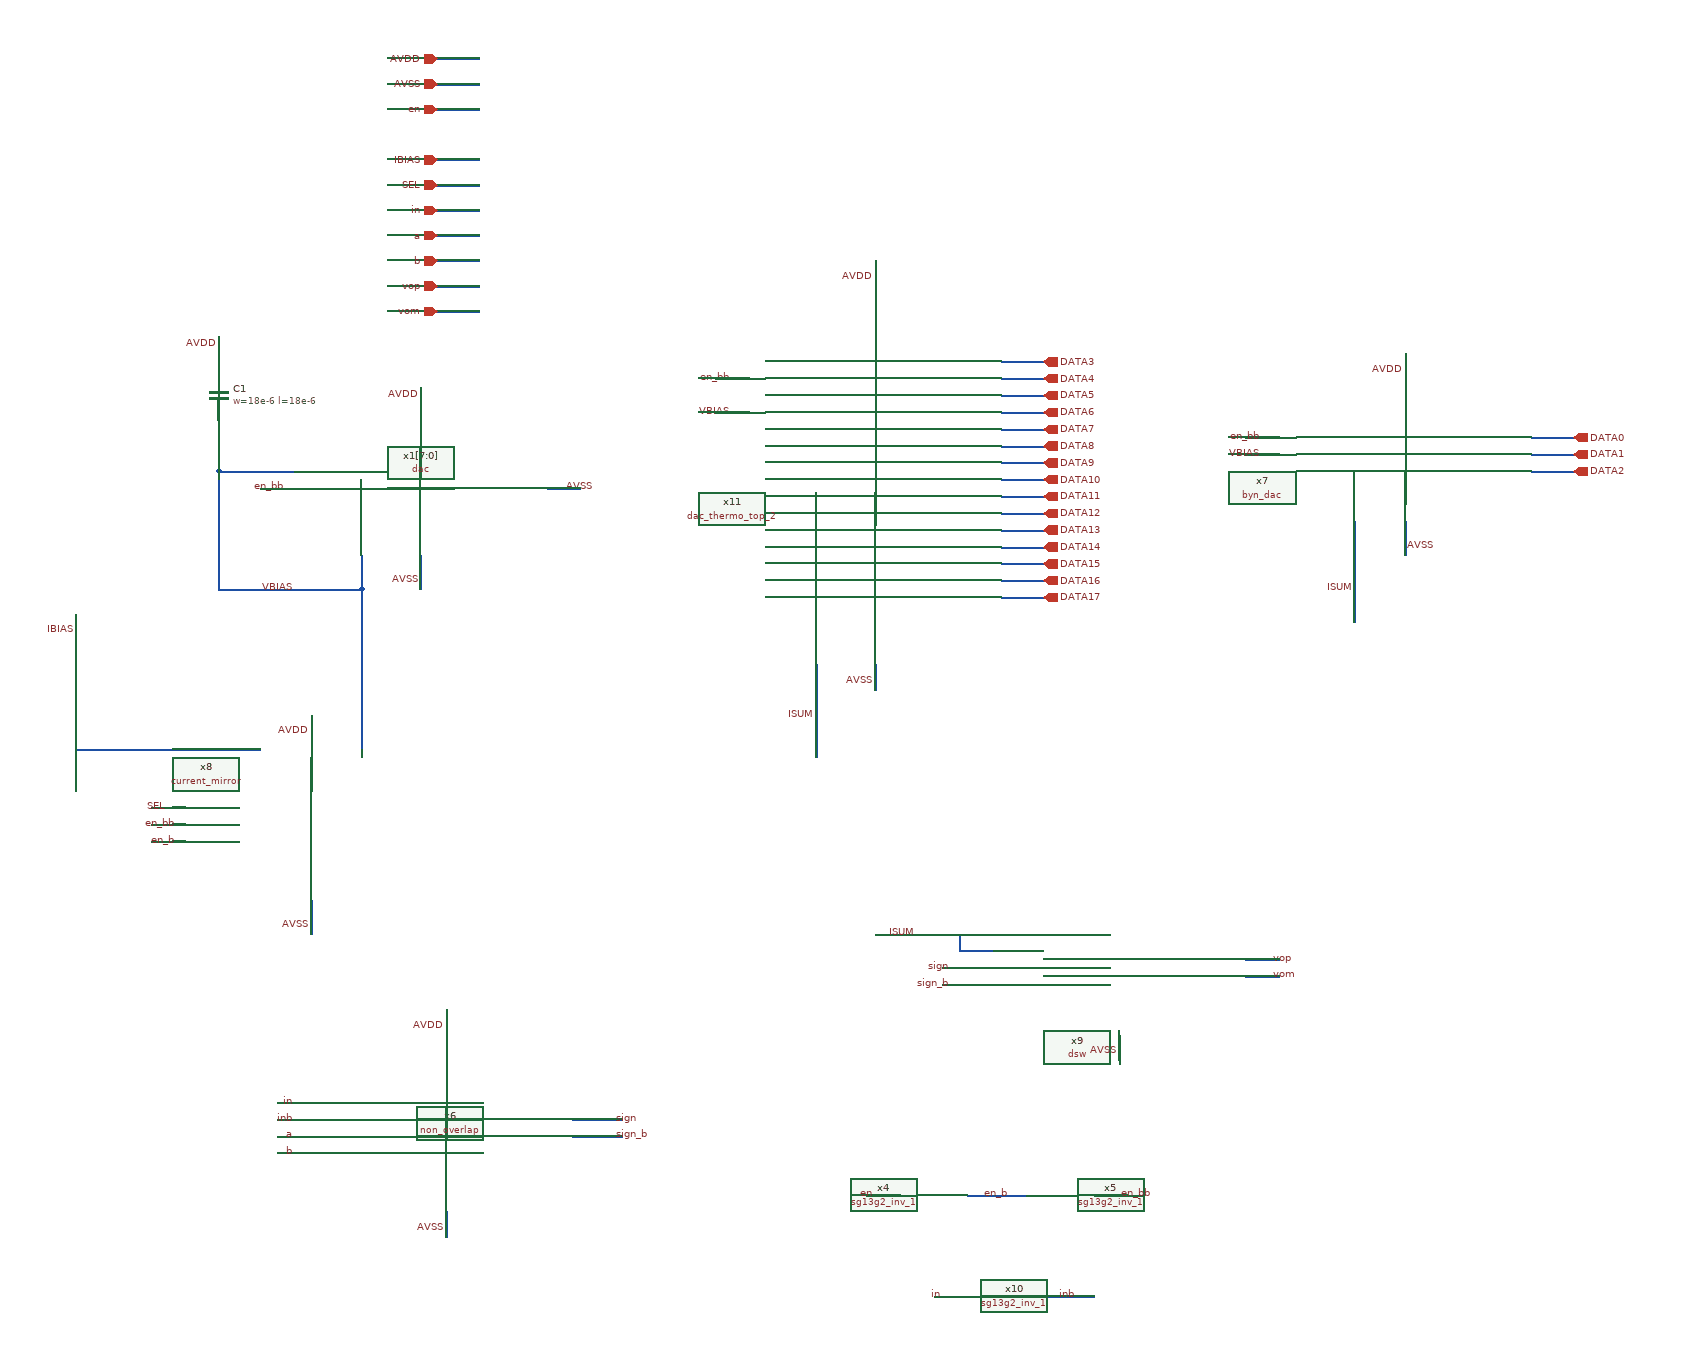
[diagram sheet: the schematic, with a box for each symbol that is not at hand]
v {xschem version=3.4.8RC file_version=1.3}
G {}
K {}
V {}
S {}
F {}
E {}
N 790 -850 790 -810 {lab=AVDD}
N 920 -1240 920 -1200 {lab=AVDD}
N 790 -630 790 -590 {lab=AVSS}
N 600 -740 640 -740 {lab=SEL}
N 600 -720 640 -720 {lab=en_bb}
N 600 -700 640 -700 {lab=en_b}
N 730 -1120 770 -1120 {lab=en_bb}
N 1070 -1120 1110 -1120 {lab=AVSS}
N 920 -1040 920 -1000 {lab=AVSS}
N 1460 -1390 1460 -1350 {lab=AVDD}
N 1270 -1210 1310 -1210 {lab=VBIAS}
N 1270 -1250 1310 -1250 {lab=en_bb}
N 1460 -910 1460 -880 {lab=AVSS}
N 1450 -280 1490 -280 {lab=en}
N 1570 -280 1640 -280 {lab=en_b}
N 1720 -280 1760 -280 {lab=en_bb}
N 680 -1140 770 -1140 {lab=VBIAS}
N 680 -1140 680 -1000 {lab=VBIAS}
N 680 -1000 850 -1000 {lab=VBIAS}
N 850 -1040 850 -1000 {lab=VBIAS}
N 1530 -160 1570 -160 {lab=in}
N 1650 -160 1720 -160 {lab=inb}
N 1100 -370 1160 -370 {lab=sign}
N 1100 -350 1160 -350 {lab=sign_b}
N 950 -260 950 -230 {lab=AVSS}
N 950 -500 950 -460 {lab=AVDD}
N 750 -390 800 -390 {lab=in}
N 750 -370 800 -370 {lab=inb}
N 750 -350 800 -350 {lab=a}
N 750 -330 800 -330 {lab=b}
N 2090 -1080 2090 -1040 {lab=AVSS}
N 2090 -1280 2090 -1240 {lab=AVDD}
N 1900 -1160 1940 -1160 {lab=VBIAS}
N 1900 -1180 1940 -1180 {lab=en_bb}
N 510 -810 730 -810 {lab=IBIAS}
N 510 -970 510 -810 {lab=IBIAS}
N 850 -1000 850 -810 {lab=VBIAS}
N 1540 -550 1600 -550 {lab=sign}
N 1540 -530 1600 -530 {lab=sign_b}
N 1900 -560 1940 -560 {lab=vop}
N 1900 -540 1940 -540 {lab=vom}
N 1750 -470 1750 -440 {lab=AVSS}
N 1560 -570 1600 -570 {lab=ISUM}
N 1560 -590 1560 -570 {lab=ISUM}
N 1390 -910 1390 -800 {lab=ISUM}
N 1460 -590 1560 -590 {lab=ISUM}
N 2030 -1080 2030 -960 {lab=ISUM}
N 940 -1630 990 -1630 {lab=AVDD}
N 940 -1600 990 -1600 {lab=AVSS}
N 1610 -1270 1660 -1270 {lab=DATA3}
N 940 -1570 990 -1570 {lab=en}
N 1610 -1250 1660 -1250 {lab=DATA4}
N 1610 -1230 1660 -1230 {lab=DATA5}
N 1610 -1210 1660 -1210 {lab=DATA6}
N 1610 -1190 1660 -1190 {lab=DATA7}
N 1610 -1170 1660 -1170 {lab=DATA8}
N 1610 -1150 1660 -1150 {lab=DATA9}
N 1610 -1130 1660 -1130 {lab=DATA10}
N 1610 -1110 1660 -1110 {lab=DATA11}
N 1610 -1090 1660 -1090 {lab=DATA12}
N 1610 -1070 1660 -1070 {lab=DATA13}
N 1610 -1050 1660 -1050 {lab=DATA14}
N 1610 -1030 1660 -1030 {lab=DATA15}
N 1610 -1010 1660 -1010 {lab=DATA16}
N 1610 -990 1660 -990 {lab=DATA17}
N 940 -1510 990 -1510 {lab=IBIAS}
N 940 -1480 990 -1480 {lab=SEL}
N 940 -1450 990 -1450 {lab=in}
N 940 -1420 990 -1420 {lab=a}
N 940 -1390 990 -1390 {lab=b}
N 940 -1360 990 -1360 {lab=vop}
N 940 -1330 990 -1330 {lab=vom}
N 2240 -1180 2290 -1180 {lab=DATA0}
N 2240 -1160 2290 -1160 {lab=DATA1}
N 2240 -1140 2290 -1140 {lab=DATA2}
N 680 -1200 680 -1140 {lab=VBIAS}
N 680 -1300 680 -1260 {lab=AVDD}
C {current_mirror.sym} 790 -720 0 0 {name=x8}
C {lab_wire.sym} 790 -830 0 0 {name=p12 sig_type=std_logic lab=AVDD}
C {lab_wire.sym} 770 -1000 0 0 {name=p13 sig_type=std_logic lab=VBIAS}
C {lab_wire.sym} 620 -740 0 0 {name=p14 sig_type=std_logic lab=SEL}
C {lab_wire.sym} 630 -720 0 0 {name=p15 sig_type=std_logic lab=en_bb}
C {lab_wire.sym} 630 -700 0 0 {name=p16 sig_type=std_logic lab=en_b}
C {lab_wire.sym} 790 -600 0 0 {name=p17 sig_type=std_logic lab=AVSS}
C {lab_wire.sym} 920 -1010 0 0 {name=p18 sig_type=std_logic lab=AVSS}
C {lab_wire.sym} 920 -1230 0 0 {name=p19 sig_type=std_logic lab=AVDD}
C {lab_wire.sym} 1460 -1370 0 0 {name=p20 sig_type=std_logic lab=AVDD}
C {lab_wire.sym} 760 -1120 0 0 {name=p21 sig_type=std_logic lab=en_bb}
C {lab_wire.sym} 1290 -1210 0 0 {name=p22 sig_type=std_logic lab=VBIAS}
C {lab_wire.sym} 1290 -1250 0 0 {name=p23 sig_type=std_logic lab=en_bb}
C {lab_wire.sym} 1090 -1120 0 1 {name=p28 sig_type=std_logic lab=AVSS}
C {sg13g2_stdcells/sg13g2_inv_1.sym} 1530 -280 0 0 {name=x4 VDD=AVDD VSS=AVSS prefix=sg13g2_ }
C {lab_wire.sym} 1460 -280 0 0 {name=p44 sig_type=std_logic lab=en}
C {sg13g2_stdcells/sg13g2_inv_1.sym} 1680 -280 0 0 {name=x5 VDD=AVDD VSS=AVSS prefix=sg13g2_ }
C {lab_wire.sym} 1620 -280 0 0 {name=p45 sig_type=std_logic lab=en_b}
C {lab_wire.sym} 510 -950 0 0 {name=p24 sig_type=std_logic lab=IBIAS}
C {lab_wire.sym} 1750 -280 0 1 {name=p50 sig_type=std_logic lab=en_bb}
C {sg13g2_stdcells/sg13g2_inv_1.sym} 1610 -160 0 0 {name=x10 VDD=AVDD VSS=AVSS prefix=sg13g2_ }
C {lab_wire.sym} 1540 -160 0 0 {name=p57 sig_type=std_logic lab=in}
C {lab_wire.sym} 1700 -160 0 0 {name=p58 sig_type=std_logic lab=inb}
C {lab_wire.sym} 1460 -890 1 1 {name=p29 sig_type=std_logic lab=AVSS}
C {lab_wire.sym} 1390 -850 0 0 {name=p26 sig_type=std_logic lab=ISUM}
C {non_overlap.sym} 950 -360 0 0 {name=x6}
C {lab_wire.sym} 1150 -370 0 1 {name=p30 sig_type=std_logic lab=sign}
C {lab_wire.sym} 1150 -350 0 1 {name=p31 sig_type=std_logic lab=sign_b}
C {lab_wire.sym} 950 -240 0 0 {name=p32 sig_type=std_logic lab=AVSS}
C {lab_wire.sym} 950 -480 0 0 {name=p33 sig_type=std_logic lab=AVDD}
C {lab_wire.sym} 770 -370 0 0 {name=p34 sig_type=std_logic lab=inb}
C {lab_wire.sym} 770 -390 0 0 {name=p35 sig_type=std_logic lab=in}
C {lab_wire.sym} 770 -350 0 0 {name=p51 sig_type=std_logic lab=a}
C {lab_wire.sym} 770 -330 0 0 {name=p52 sig_type=std_logic lab=b}
C {byn_dac.sym} 2090 -1160 0 0 {name=x7}
C {lab_wire.sym} 2090 -1050 0 1 {name=p53 sig_type=std_logic lab=AVSS}
C {lab_wire.sym} 2090 -1260 0 0 {name=p54 sig_type=std_logic lab=AVDD}
C {lab_wire.sym} 1920 -1160 0 0 {name=p59 sig_type=std_logic lab=VBIAS}
C {lab_wire.sym} 1920 -1180 0 0 {name=p66 sig_type=std_logic lab=en_bb}
C {lab_wire.sym} 2030 -1000 0 0 {name=p67 sig_type=std_logic lab=ISUM}
C {lab_wire.sym} 1930 -560 0 1 {name=p68 sig_type=std_logic lab=vop}
C {dsw.sym} 1750 -550 0 0 {name=x9}
C {lab_wire.sym} 1930 -540 0 1 {name=p107 sig_type=std_logic lab=vom}
C {lab_wire.sym} 1750 -450 0 0 {name=p108 sig_type=std_logic lab=AVSS}
C {lab_wire.sym} 1550 -550 0 0 {name=p109 sig_type=std_logic lab=sign}
C {lab_wire.sym} 1550 -530 0 0 {name=p110 sig_type=std_logic lab=sign_b}
C {lab_wire.sym} 1510 -590 0 0 {name=p113 sig_type=std_logic lab=ISUM}
C {dac_thermo_top_2.sym} 1460 -1140 0 0 {name=x11}
C {dac.sym} 920 -1120 0 0 {name=x1[7:0]}
C {iopin.sym} 940 -1630 2 0 {name=p721 lab=AVDD}
C {iopin.sym} 940 -1600 2 0 {name=p722 lab=AVSS}
C {iopin.sym} 940 -1570 2 0 {name=p724 lab=en}
C {iopin.sym} 1660 -1250 2 1 {name=p725 lab=DATA4}
C {iopin.sym} 1660 -1270 2 1 {name=p727 lab=DATA3}
C {iopin.sym} 1660 -1230 2 1 {name=p728 lab=DATA5}
C {iopin.sym} 1660 -1190 2 1 {name=p729 lab=DATA7}
C {iopin.sym} 1660 -1210 2 1 {name=p730 lab=DATA6}
C {iopin.sym} 1660 -1170 2 1 {name=p731 lab=DATA8}
C {iopin.sym} 1660 -1150 2 1 {name=p732 lab=DATA9}
C {iopin.sym} 1660 -1130 2 1 {name=p733 lab=DATA10}
C {iopin.sym} 1660 -1090 2 1 {name=p734 lab=DATA12}
C {iopin.sym} 1660 -1110 2 1 {name=p735 lab=DATA11}
C {iopin.sym} 1660 -1070 2 1 {name=p736 lab=DATA13}
C {iopin.sym} 1660 -1050 2 1 {name=p737 lab=DATA14}
C {iopin.sym} 1660 -1030 2 1 {name=p738 lab=DATA15}
C {iopin.sym} 1660 -1010 2 1 {name=p739 lab=DATA16}
C {iopin.sym} 1660 -990 2 1 {name=p740 lab=DATA17}
C {iopin.sym} 940 -1510 2 0 {name=p1 lab=IBIAS}
C {iopin.sym} 940 -1480 2 0 {name=p2 lab=SEL}
C {iopin.sym} 940 -1450 2 0 {name=p3 lab=in}
C {iopin.sym} 940 -1420 2 0 {name=p4 lab=a}
C {iopin.sym} 940 -1390 2 0 {name=p5 lab=b}
C {iopin.sym} 940 -1360 2 0 {name=p6 lab=vop}
C {iopin.sym} 940 -1330 2 0 {name=p7 lab=vom}
C {iopin.sym} 2290 -1160 2 1 {name=p8 lab=DATA1}
C {iopin.sym} 2290 -1180 2 1 {name=p9 lab=DATA0}
C {iopin.sym} 2290 -1140 2 1 {name=p10 lab=DATA2}
C {sg13g2_pr/cap_cmim.sym} 680 -1230 0 0 {name=C1
model=cap_cmim
w=18e-6
l=18e-6
m=80
spiceprefix=X}
C {lab_wire.sym} 680 -1290 0 0 {name=p25 sig_type=std_logic lab=AVDD}
